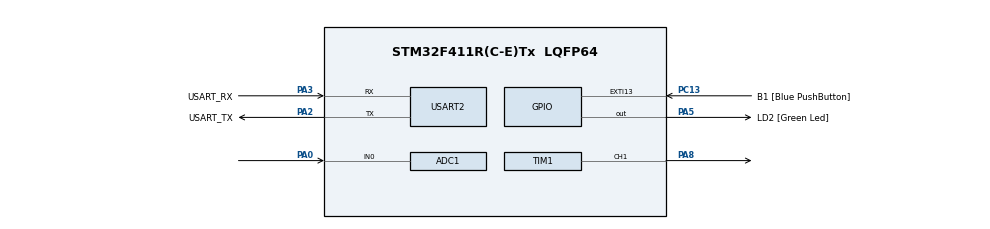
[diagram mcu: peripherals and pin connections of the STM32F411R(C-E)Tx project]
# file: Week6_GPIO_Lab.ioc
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ADC1.Channel-0\#ChannelRegularConversion=ADC_CHANNEL_0
ADC1.ExternalTrigConv=ADC_EXTERNALTRIGCONV_T3_TRGO
ADC1.NbrOfConversionFlag=1
ADC1.Rank-0\#ChannelRegularConversion=1
ADC1.SamplingTime-0\#ChannelRegularConversion=ADC_SAMPLETIME_3CYCLES
ADC1.master=1
Mcu.Family=STM32F4
Mcu.Name=STM32F411R(C-E)Tx
Mcu.Package=LQFP64
NVIC.ADC_IRQn=true\:0\:0\:false\:false\:true\:true\:true
NVIC.PriorityGroup=NVIC_PRIORITYGROUP_0
NVIC.TIM1_TRG_COM_TIM11_IRQn=true\:0\:0\:false\:false\:true\:true\:true
PA0-WKUP.Signal=ADCx_IN0
PA13.GPIO_Label=TMS
PA13.Mode=Serial_Wire
PA13.Signal=SYS_JTMS-SWDIO
PA14.GPIO_Label=TCK
PA14.Mode=Serial_Wire
PA14.Signal=SYS_JTCK-SWCLK
PA2.GPIO_Label=USART_TX
PA2.Mode=Asynchronous
PA2.Signal=USART2_TX
PA3.GPIO_Label=USART_RX
PA3.Mode=Asynchronous
PA3.Signal=USART2_RX
PA5.GPIO_Label=LD2 [Green Led]
PA5.Signal=GPIO_Output
PA8.Signal=S_TIM1_CH1
PB3.GPIO_Label=SWO
PB3.Signal=SYS_JTDO-SWO
PC13-ANTI_TAMP.GPIO_Label=B1 [Blue PushButton]
PC13-ANTI_TAMP.GPIO_ModeDefaultEXTI=GPIO_MODE_IT_FALLING
PC13-ANTI_TAMP.Signal=GPXTI13
PC14-OSC32_IN.Mode=LSE-External-Oscillator
PC14-OSC32_IN.Signal=RCC_OSC32_IN
PC15-OSC32_OUT.Mode=LSE-External-Oscillator
PC15-OSC32_OUT.Signal=RCC_OSC32_OUT
PH0\ -\ OSC_IN.Mode=HSE-External-Clock-Source
PH0\ -\ OSC_IN.Signal=RCC_OSC_IN
PH1\ -\ OSC_OUT.Mode=HSE-External-Clock-Source
PH1\ -\ OSC_OUT.Signal=RCC_OSC_OUT
ProjectManager.HeapSize=0x200
ProjectManager.StackSize=0x400
ProjectManager.TargetToolchain=STM32CubeIDE
RCC.48MHZClocksFreq_Value=84000000
RCC.AHBFreq_Value=84000000
RCC.APB1CLKDivider=RCC_HCLK_DIV2
RCC.APB1Freq_Value=42000000
RCC.APB1TimFreq_Value=84000000
RCC.APB2Freq_Value=84000000
RCC.APB2TimFreq_Value=84000000
RCC.CortexFreq_Value=84000000
RCC.FLatency-AdvancedSettings=FLASH_LATENCY_2
RCC.HCLKFreq_Value=84000000
RCC.HSE_VALUE=8000000
RCC.HSI_VALUE=16000000
RCC.PLLN=336
RCC.PLLP=RCC_PLLP_DIV4
RCC.SYSCLKFreq_VALUE=84000000
RCC.SYSCLKSource=RCC_SYSCLKSOURCE_PLLCLK
RCC.VCOOutputFreq_Value=336000000
SH.ADCx_IN0.0=ADC1_IN0,IN0
SH.S_TIM1_CH1.0=TIM1_CH1,PWM Generation1 CH1
TIM1.Channel-PWM\ Generation1\ CH1=TIM_CHANNEL_1
TIM1.Period=10000
TIM11.Prescaler=99
TIM3.Period=1000
TIM3.TIM_MasterOutputTrigger=TIM_TRGO_UPDATE
USART2.VirtualMode=VM_ASYNC
VP_TIM11_VS_ClockSourceINT.Mode=Enable_Timer
VP_TIM1_VS_ClockSourceINT.Mode=Internal
VP_TIM3_VS_ClockSourceINT.Mode=Internal
board=NUCLEO-F411RE

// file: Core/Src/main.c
/* USER CODE BEGIN Header */
/**
 ******************************************************************************
 * @file           : main.c
 * @brief          : Main program body
 ******************************************************************************
 * @attention
 *
 * <h2><center>&copy; Copyright (c) 2021 STMicroelectronics.
 * All rights reserved.</center></h2>
 *
 * This software component is licensed by ST under BSD 3-Clause license,
 * the "License"; You may not use this file except in compliance with the
 * License. You may obtain a copy of the License at:
 *                        opensource.org/licenses/BSD-3-Clause
 *
 ******************************************************************************
 */
/* USER CODE END Header */
#include "main.h"

ADC_HandleTypeDef hadc1;

TIM_HandleTypeDef htim1;
TIM_HandleTypeDef htim3;
TIM_HandleTypeDef htim11;

UART_HandleTypeDef huart2;

/* USER CODE BEGIN PV */
uint16_t Setpoint =1241 ;				//PA8/3.3V = 4095/3.3
uint8_t ADCUpdateFlag = 0;
//Store ADC Value
uint8_t ADCFeedBack = 0;
uint8_t Kp=0;
uint8_t Error=0;
uint16_t PWMOut = 3000;

uint64_t _micro = 0;
uint64_t TimeOutputLoop = 0;
/* USER CODE END PV */

void SystemClock_Config(void);
static void MX_GPIO_Init(void);
static void MX_USART2_UART_Init(void);
static void MX_ADC1_Init(void);
static void MX_TIM1_Init(void);
static void MX_TIM11_Init(void);
static void MX_TIM3_Init(void);
/* USER CODE BEGIN PFP */
uint64_t micros();
/* USER CODE END PFP */

int main(void)
{

  /* MCU Configuration--------------------------------------------------------*/

  /* Reset of all peripherals, Initializes the Flash interface and the Systick. */
  HAL_Init();

  /* Configure the system clock */
  SystemClock_Config();

  /* Initialize all configured peripherals */
  MX_GPIO_Init();
  MX_USART2_UART_Init();
  MX_ADC1_Init();
  MX_TIM1_Init();
  MX_TIM11_Init();
  MX_TIM3_Init();
  /* USER CODE BEGIN 2 */
	//ADC START
	HAL_ADC_Start_IT(&hadc1);
	HAL_TIM_Base_Start(&htim3);
	// start pwm
	HAL_TIM_Base_Start(&htim1);
	HAL_TIM_PWM_Start(&htim1, TIM_CHANNEL_1);
	// start micros
	HAL_TIM_Base_Start_IT(&htim11);

  /* USER CODE END 2 */

  /* Infinite loop */
	while (1)
	{

    /* USER CODE BEGIN 3 */

		//1 Khz Loop
		if (micros() - TimeOutputLoop >= 1000)//uS
		{
			TimeOutputLoop = micros();
			// #001
			Error = Setpoint- ADCFeedBack ;
			PWMOut = Kp * Error ;
			__HAL_TIM_SET_COMPARE(&htim1, TIM_CHANNEL_1, PWMOut);

		}

		if (ADCUpdateFlag)
		{
			ADCUpdateFlag = 0;
			//#002
		}

	}
  /* USER CODE END 3 */
}

void SystemClock_Config(void)
{
  RCC_OscInitTypeDef RCC_OscInitStruct = {0};
  RCC_ClkInitTypeDef RCC_ClkInitStruct = {0};

  /** Configure the main internal regulator output voltage
  */
  __HAL_RCC_PWR_CLK_ENABLE();
  __HAL_PWR_VOLTAGESCALING_CONFIG(PWR_REGULATOR_VOLTAGE_SCALE1);
  /** Initializes the RCC Oscillators according to the specified parameters
  * in the RCC_OscInitTypeDef structure.
  */
  RCC_OscInitStruct.OscillatorType = RCC_OSCILLATORTYPE_HSI;
  RCC_OscInitStruct.HSIState = RCC_HSI_ON;
  RCC_OscInitStruct.HSICalibrationValue = RCC_HSICALIBRATION_DEFAULT;
  RCC_OscInitStruct.PLL.PLLState = RCC_PLL_ON;
  RCC_OscInitStruct.PLL.PLLSource = RCC_PLLSOURCE_HSI;
  RCC_OscInitStruct.PLL.PLLM = 8;
  RCC_OscInitStruct.PLL.PLLN = 100;
  RCC_OscInitStruct.PLL.PLLP = RCC_PLLP_DIV2;
  RCC_OscInitStruct.PLL.PLLQ = 4;
  if (HAL_RCC_OscConfig(&RCC_OscInitStruct) != HAL_OK)
  {
    Error_Handler();
  }
  /** Initializes the CPU, AHB and APB buses clocks
  */
  RCC_ClkInitStruct.ClockType = RCC_CLOCKTYPE_HCLK|RCC_CLOCKTYPE_SYSCLK
                              |RCC_CLOCKTYPE_PCLK1|RCC_CLOCKTYPE_PCLK2;
  RCC_ClkInitStruct.SYSCLKSource = RCC_SYSCLKSOURCE_PLLCLK;
  RCC_ClkInitStruct.AHBCLKDivider = RCC_SYSCLK_DIV1;
  RCC_ClkInitStruct.APB1CLKDivider = RCC_HCLK_DIV2;
  RCC_ClkInitStruct.APB2CLKDivider = RCC_HCLK_DIV1;

  if (HAL_RCC_ClockConfig(&RCC_ClkInitStruct, FLASH_LATENCY_3) != HAL_OK)
  {
    Error_Handler();
  }
}

static void MX_ADC1_Init(void)
{

  ADC_ChannelConfTypeDef sConfig = {0};

  /** Configure the global features of the ADC (Clock, Resolution, Data Alignment and number of conversion)
  */
  hadc1.Instance = ADC1;
  hadc1.Init.ClockPrescaler = ADC_CLOCK_SYNC_PCLK_DIV4;
  hadc1.Init.Resolution = ADC_RESOLUTION_12B;
  hadc1.Init.ScanConvMode = DISABLE;
  hadc1.Init.ContinuousConvMode = DISABLE;
  hadc1.Init.DiscontinuousConvMode = DISABLE;
  hadc1.Init.ExternalTrigConvEdge = ADC_EXTERNALTRIGCONVEDGE_RISING;
  hadc1.Init.ExternalTrigConv = ADC_EXTERNALTRIGCONV_T3_TRGO;
  hadc1.Init.DataAlign = ADC_DATAALIGN_RIGHT;
  hadc1.Init.NbrOfConversion = 1;
  hadc1.Init.DMAContinuousRequests = DISABLE;
  hadc1.Init.EOCSelection = ADC_EOC_SINGLE_CONV;
  if (HAL_ADC_Init(&hadc1) != HAL_OK)
  {
    Error_Handler();
  }
  /** Configure for the selected ADC regular channel its corresponding rank in the sequencer and its sample time.
  */
  sConfig.Channel = ADC_CHANNEL_0;
  sConfig.Rank = 1;
  sConfig.SamplingTime = ADC_SAMPLETIME_56CYCLES;
  if (HAL_ADC_ConfigChannel(&hadc1, &sConfig) != HAL_OK)
  {
    Error_Handler();
  }

}

static void MX_TIM1_Init(void)
{

  TIM_ClockConfigTypeDef sClockSourceConfig = {0};
  TIM_MasterConfigTypeDef sMasterConfig = {0};
  TIM_OC_InitTypeDef sConfigOC = {0};
  TIM_BreakDeadTimeConfigTypeDef sBreakDeadTimeConfig = {0};

  htim1.Instance = TIM1;
  htim1.Init.Prescaler = 0;
  htim1.Init.CounterMode = TIM_COUNTERMODE_UP;
  htim1.Init.Period = 10000;
  htim1.Init.ClockDivision = TIM_CLOCKDIVISION_DIV1;
  htim1.Init.RepetitionCounter = 0;
  htim1.Init.AutoReloadPreload = TIM_AUTORELOAD_PRELOAD_ENABLE;
  if (HAL_TIM_Base_Init(&htim1) != HAL_OK)
  {
    Error_Handler();
  }
  sClockSourceConfig.ClockSource = TIM_CLOCKSOURCE_INTERNAL;
  if (HAL_TIM_ConfigClockSource(&htim1, &sClockSourceConfig) != HAL_OK)
  {
    Error_Handler();
  }
  if (HAL_TIM_PWM_Init(&htim1) != HAL_OK)
  {
    Error_Handler();
  }
  sMasterConfig.MasterOutputTrigger = TIM_TRGO_RESET;
  sMasterConfig.MasterSlaveMode = TIM_MASTERSLAVEMODE_DISABLE;
  if (HAL_TIMEx_MasterConfigSynchronization(&htim1, &sMasterConfig) != HAL_OK)
  {
    Error_Handler();
  }
  sConfigOC.OCMode = TIM_OCMODE_PWM1;
  sConfigOC.Pulse = 0;
  sConfigOC.OCPolarity = TIM_OCPOLARITY_HIGH;
  sConfigOC.OCNPolarity = TIM_OCNPOLARITY_HIGH;
  sConfigOC.OCFastMode = TIM_OCFAST_DISABLE;
  sConfigOC.OCIdleState = TIM_OCIDLESTATE_RESET;
  sConfigOC.OCNIdleState = TIM_OCNIDLESTATE_RESET;
  if (HAL_TIM_PWM_ConfigChannel(&htim1, &sConfigOC, TIM_CHANNEL_1) != HAL_OK)
  {
    Error_Handler();
  }
  sBreakDeadTimeConfig.OffStateRunMode = TIM_OSSR_DISABLE;
  sBreakDeadTimeConfig.OffStateIDLEMode = TIM_OSSI_DISABLE;
  sBreakDeadTimeConfig.LockLevel = TIM_LOCKLEVEL_OFF;
  sBreakDeadTimeConfig.DeadTime = 0;
  sBreakDeadTimeConfig.BreakState = TIM_BREAK_DISABLE;
  sBreakDeadTimeConfig.BreakPolarity = TIM_BREAKPOLARITY_HIGH;
  sBreakDeadTimeConfig.AutomaticOutput = TIM_AUTOMATICOUTPUT_DISABLE;
  if (HAL_TIMEx_ConfigBreakDeadTime(&htim1, &sBreakDeadTimeConfig) != HAL_OK)
  {
    Error_Handler();
  }
  HAL_TIM_MspPostInit(&htim1);

}

static void MX_TIM3_Init(void)
{

  TIM_ClockConfigTypeDef sClockSourceConfig = {0};
  TIM_MasterConfigTypeDef sMasterConfig = {0};

  htim3.Instance = TIM3;
  htim3.Init.Prescaler = 99;
  htim3.Init.CounterMode = TIM_COUNTERMODE_UP;
  htim3.Init.Period = 1000;
  htim3.Init.ClockDivision = TIM_CLOCKDIVISION_DIV1;
  htim3.Init.AutoReloadPreload = TIM_AUTORELOAD_PRELOAD_DISABLE;
  if (HAL_TIM_Base_Init(&htim3) != HAL_OK)
  {
    Error_Handler();
  }
  sClockSourceConfig.ClockSource = TIM_CLOCKSOURCE_INTERNAL;
  if (HAL_TIM_ConfigClockSource(&htim3, &sClockSourceConfig) != HAL_OK)
  {
    Error_Handler();
  }
  sMasterConfig.MasterOutputTrigger = TIM_TRGO_UPDATE;
  sMasterConfig.MasterSlaveMode = TIM_MASTERSLAVEMODE_DISABLE;
  if (HAL_TIMEx_MasterConfigSynchronization(&htim3, &sMasterConfig) != HAL_OK)
  {
    Error_Handler();
  }

}

static void MX_TIM11_Init(void)
{

  htim11.Instance = TIM11;
  htim11.Init.Prescaler = 99;
  htim11.Init.CounterMode = TIM_COUNTERMODE_UP;
  htim11.Init.Period = 65535;
  htim11.Init.ClockDivision = TIM_CLOCKDIVISION_DIV1;
  htim11.Init.AutoReloadPreload = TIM_AUTORELOAD_PRELOAD_DISABLE;
  if (HAL_TIM_Base_Init(&htim11) != HAL_OK)
  {
    Error_Handler();
  }

}

static void MX_USART2_UART_Init(void)
{

  huart2.Instance = USART2;
  huart2.Init.BaudRate = 115200;
  huart2.Init.WordLength = UART_WORDLENGTH_8B;
  huart2.Init.StopBits = UART_STOPBITS_1;
  huart2.Init.Parity = UART_PARITY_NONE;
  huart2.Init.Mode = UART_MODE_TX_RX;
  huart2.Init.HwFlowCtl = UART_HWCONTROL_NONE;
  huart2.Init.OverSampling = UART_OVERSAMPLING_16;
  if (HAL_UART_Init(&huart2) != HAL_OK)
  {
    Error_Handler();
  }

}

static void MX_GPIO_Init(void)
{
  GPIO_InitTypeDef GPIO_InitStruct = {0};

  /* GPIO Ports Clock Enable */
  __HAL_RCC_GPIOC_CLK_ENABLE();
  __HAL_RCC_GPIOH_CLK_ENABLE();
  __HAL_RCC_GPIOA_CLK_ENABLE();
  __HAL_RCC_GPIOB_CLK_ENABLE();

  /*Configure GPIO pin Output Level */
  HAL_GPIO_WritePin(LD2_GPIO_Port, LD2_Pin, GPIO_PIN_RESET);

  /*Configure GPIO pin : B1_Pin */
  GPIO_InitStruct.Pin = B1_Pin;
  GPIO_InitStruct.Mode = GPIO_MODE_IT_FALLING;
  GPIO_InitStruct.Pull = GPIO_NOPULL;
  HAL_GPIO_Init(B1_GPIO_Port, &GPIO_InitStruct);

  /*Configure GPIO pin : LD2_Pin */
  GPIO_InitStruct.Pin = LD2_Pin;
  GPIO_InitStruct.Mode = GPIO_MODE_OUTPUT_PP;
  GPIO_InitStruct.Pull = GPIO_NOPULL;
  GPIO_InitStruct.Speed = GPIO_SPEED_FREQ_LOW;
  HAL_GPIO_Init(LD2_GPIO_Port, &GPIO_InitStruct);

}

/* USER CODE BEGIN 4 */

void HAL_ADC_ConvCpltCallback(ADC_HandleTypeDef *hadc)
{
	ADCFeedBack = HAL_ADC_GetValue(&hadc1);
	ADCUpdateFlag = 1;
}
void HAL_TIM_PeriodElapsedCallback(TIM_HandleTypeDef *htim)
{
	if (htim == &htim11)
	{
		_micro += 65535;
	}
}

__inline__ uint64_t micros()
{
	return _micro + htim11.Instance->CNT;
}
/* USER CODE END 4 */

void Error_Handler(void)
{
	__disable_irq();
	while (1)
	{
	}
}

/************************ (C) COPYRIGHT STMicroelectronics *****END OF FILE****/
